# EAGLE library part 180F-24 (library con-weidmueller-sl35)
WEIDMUELLER CLAMP CONNECTOR

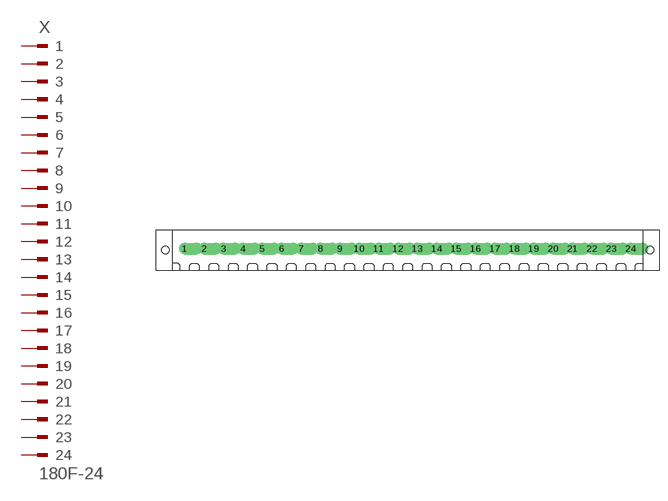
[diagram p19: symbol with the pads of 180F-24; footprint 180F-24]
Designator prefix X

## 180F-24  [180F-24]
1  1  pas
2  2  pas
3  3  pas
4  4  pas
5  5  pas
6  6  pas
7  7  pas
8  8  pas
9  9  pas
10  10  pas
11  11  pas
12  12  pas
13  13  pas
14  14  pas
15  15  pas
16  16  pas
17  17  pas
18  18  pas
19  19  pas
20  20  pas
21  21  pas
22  22  pas
23  23  pas
24  24  pas

## Footprint 180F-24 (pad centres in mm)
WEIDMUELLER CLAMP CONNECTOR
drill 1.422 offset: 1 -40.25,0; 2 -36.75,0; 3 -33.25,0; 4 -29.75,0; 5 -26.25,0; 6 -22.75,0; 7 -19.25,0; 8 -15.75,0; 9 -12.25,0; 10 -8.75,0; 11 -5.25,0; 12 -1.75,0; 13 1.75,0; 14 5.25,0; 15 8.75,0; 16 12.25,0; 17 15.75,0; 18 19.25,0; 19 22.75,0; 20 26.25,0; 21 29.75,0; 22 33.25,0; 23 36.75,0; 24 40.25,0
hole 1.422 at -43.75,-0.25
hole 1.422 at 43.75,-0.25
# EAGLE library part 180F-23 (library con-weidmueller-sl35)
WEIDMUELLER CLAMP CONNECTOR

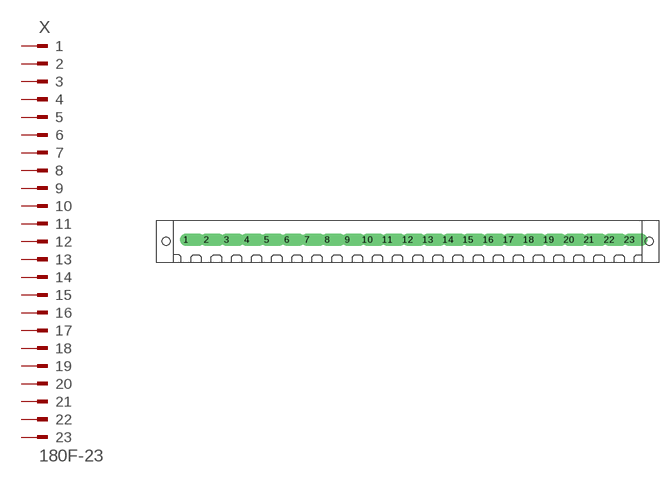
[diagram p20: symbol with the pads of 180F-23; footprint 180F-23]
Designator prefix X

## 180F-23  [180F-23]
1  1  pas
2  2  pas
3  3  pas
4  4  pas
5  5  pas
6  6  pas
7  7  pas
8  8  pas
9  9  pas
10  10  pas
11  11  pas
12  12  pas
13  13  pas
14  14  pas
15  15  pas
16  16  pas
17  17  pas
18  18  pas
19  19  pas
20  20  pas
21  21  pas
22  22  pas
23  23  pas

## Footprint 180F-23 (pad centres in mm)
WEIDMUELLER CLAMP CONNECTOR
drill 1.422 offset: 1 -38.5,0; 2 -35,0; 3 -31.5,0; 4 -28,0; 5 -24.5,0; 6 -21,0; 7 -17.5,0; 8 -14,0; 9 -10.5,0; 10 -7,0; 11 -3.5,0; 12 0,0; 13 3.5,0; 14 7,0; 15 10.5,0; 16 14,0; 17 17.5,0; 18 21,0; 19 24.5,0; 20 28,0; 21 31.5,0; 22 35,0; 23 38.5,0
hole 1.422 at -42,-0.25
hole 1.422 at 42,-0.25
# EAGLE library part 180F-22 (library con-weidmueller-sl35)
WEIDMUELLER CLAMP CONNECTOR

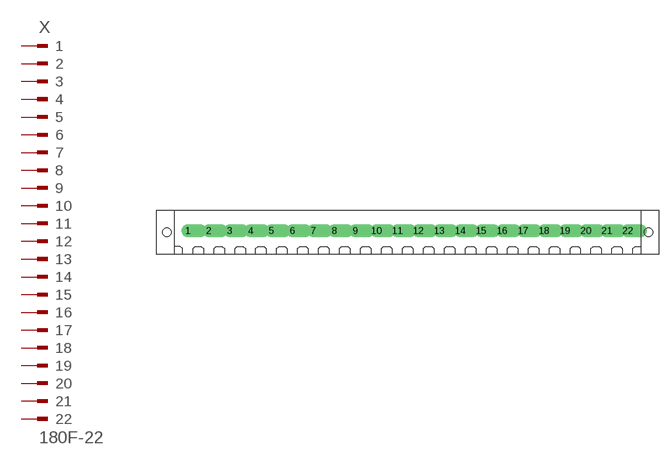
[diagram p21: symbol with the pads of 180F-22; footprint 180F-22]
Designator prefix X

## 180F-22  [180F-22]
1  1  pas
2  2  pas
3  3  pas
4  4  pas
5  5  pas
6  6  pas
7  7  pas
8  8  pas
9  9  pas
10  10  pas
11  11  pas
12  12  pas
13  13  pas
14  14  pas
15  15  pas
16  16  pas
17  17  pas
18  18  pas
19  19  pas
20  20  pas
21  21  pas
22  22  pas

## Footprint 180F-22 (pad centres in mm)
WEIDMUELLER CLAMP CONNECTOR
drill 1.422 offset: 1 -36.75,0; 2 -33.25,0; 3 -29.75,0; 4 -26.25,0; 5 -22.75,0; 6 -19.25,0; 7 -15.75,0; 8 -12.25,0; 9 -8.75,0; 10 -5.25,0; 11 -1.75,0; 12 1.75,0; 13 5.25,0; 14 8.75,0; 15 12.25,0; 16 15.75,0; 17 19.25,0; 18 22.75,0; 19 26.25,0; 20 29.75,0; 21 33.25,0; 22 36.75,0
hole 1.422 at -40.25,-0.25
hole 1.422 at 40.25,-0.25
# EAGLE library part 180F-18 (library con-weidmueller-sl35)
WEIDMUELLER CLAMP CONNECTOR

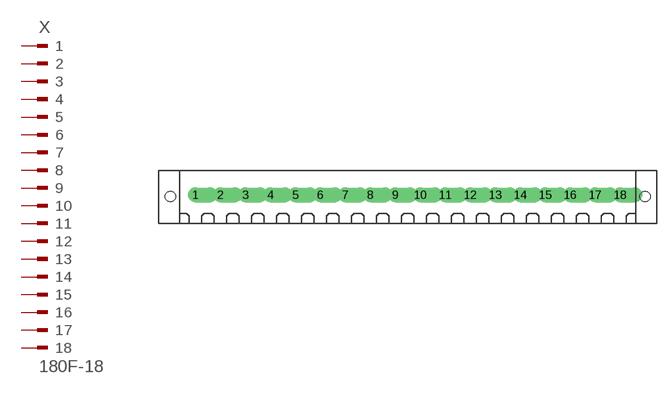
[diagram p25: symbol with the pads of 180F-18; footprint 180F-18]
Designator prefix X

## 180F-18  [180F-18]
1  1  pas
2  2  pas
3  3  pas
4  4  pas
5  5  pas
6  6  pas
7  7  pas
8  8  pas
9  9  pas
10  10  pas
11  11  pas
12  12  pas
13  13  pas
14  14  pas
15  15  pas
16  16  pas
17  17  pas
18  18  pas

## Footprint 180F-18 (pad centres in mm)
WEIDMUELLER CLAMP CONNECTOR
drill 1.422 offset: 1 -29.75,0; 2 -26.25,0; 3 -22.75,0; 4 -19.25,0; 5 -15.75,0; 6 -12.25,0; 7 -8.75,0; 8 -5.25,0; 9 -1.75,0; 10 1.75,0; 11 5.25,0; 12 8.75,0; 13 12.25,0; 14 15.75,0; 15 19.25,0; 16 22.75,0; 17 26.25,0; 18 29.75,0
hole 1.422 at -33.25,-0.25
hole 1.422 at 33.25,-0.25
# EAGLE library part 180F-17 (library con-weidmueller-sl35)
WEIDMUELLER CLAMP CONNECTOR

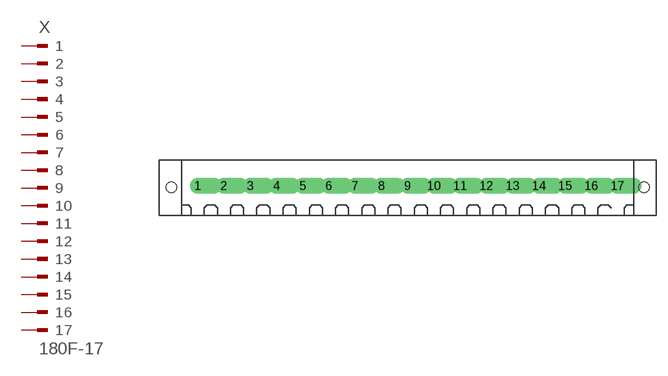
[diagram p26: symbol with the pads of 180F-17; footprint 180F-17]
Designator prefix X

## 180F-17  [180F-17]
1  1  pas
2  2  pas
3  3  pas
4  4  pas
5  5  pas
6  6  pas
7  7  pas
8  8  pas
9  9  pas
10  10  pas
11  11  pas
12  12  pas
13  13  pas
14  14  pas
15  15  pas
16  16  pas
17  17  pas

## Footprint 180F-17 (pad centres in mm)
WEIDMUELLER CLAMP CONNECTOR
drill 1.422 offset: 1 -28,0; 2 -24.5,0; 3 -21,0; 4 -17.5,0; 5 -14,0; 6 -10.5,0; 7 -7,0; 8 -3.5,0; 9 0,0; 10 3.5,0; 11 7,0; 12 10.5,0; 13 14,0; 14 17.5,0; 15 21,0; 16 24.5,0; 17 28,0
hole 1.422 at -31.5,-0.25
hole 1.422 at 31.5,-0.25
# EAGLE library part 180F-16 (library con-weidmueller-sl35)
WEIDMUELLER CLAMP CONNECTOR

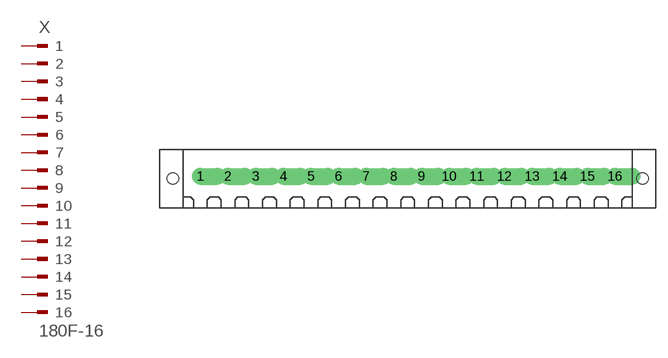
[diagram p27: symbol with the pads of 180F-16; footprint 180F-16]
Designator prefix X

## 180F-16  [180F-16]
1  1  pas
2  2  pas
3  3  pas
4  4  pas
5  5  pas
6  6  pas
7  7  pas
8  8  pas
9  9  pas
10  10  pas
11  11  pas
12  12  pas
13  13  pas
14  14  pas
15  15  pas
16  16  pas

## Footprint 180F-16 (pad centres in mm)
WEIDMUELLER CLAMP CONNECTOR
drill 1.422 offset: 1 -26.25,0; 2 -22.75,0; 3 -19.25,0; 4 -15.75,0; 5 -12.25,0; 6 -8.75,0; 7 -5.25,0; 8 -1.75,0; 9 1.75,0; 10 5.25,0; 11 8.75,0; 12 12.25,0; 13 15.75,0; 14 19.25,0; 15 22.75,0; 16 26.25,0
hole 1.422 at -29.75,-0.25
hole 1.422 at 29.75,-0.25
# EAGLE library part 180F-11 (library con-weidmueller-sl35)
WEIDMUELLER CLAMP CONNECTOR

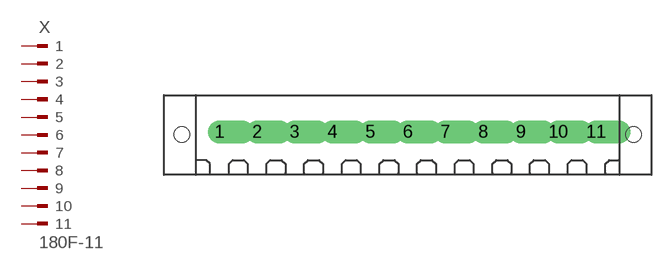
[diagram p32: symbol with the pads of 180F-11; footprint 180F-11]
Designator prefix X

## 180F-11  [180F-11]
1  1  pas
2  2  pas
3  3  pas
4  4  pas
5  5  pas
6  6  pas
7  7  pas
8  8  pas
9  9  pas
10  10  pas
11  11  pas

## Footprint 180F-11 (pad centres in mm)
WEIDMUELLER CLAMP CONNECTOR
drill 1.422 offset: 1 -17.5,0; 2 -14,0; 3 -10.5,0; 4 -7,0; 5 -3.5,0; 6 0,0; 7 3.5,0; 8 7,0; 9 10.5,0; 10 14,0; 11 17.5,0
hole 1.422 at -21,-0.25
hole 1.422 at 21,-0.25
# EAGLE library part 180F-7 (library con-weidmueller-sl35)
WEIDMUELLER CLAMP CONNECTOR

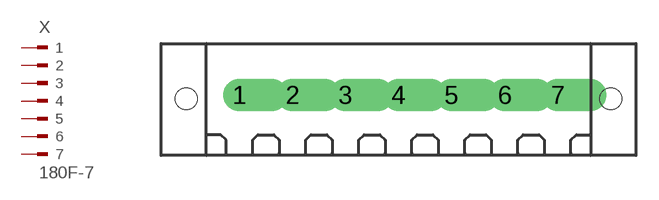
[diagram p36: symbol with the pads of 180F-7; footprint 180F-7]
Designator prefix X

## 180F-7  [180F-7]
1  1  pas
2  2  pas
3  3  pas
4  4  pas
5  5  pas
6  6  pas
7  7  pas

## Footprint 180F-7 (pad centres in mm)
WEIDMUELLER CLAMP CONNECTOR
drill 1.422 offset: 1 -10.5,0; 2 -7,0; 3 -3.5,0; 4 0,0; 5 3.5,0; 6 7,0; 7 10.5,0
hole 1.422 at -14,-0.25
hole 1.422 at 14,-0.25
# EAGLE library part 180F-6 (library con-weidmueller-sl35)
WEIDMUELLER CLAMP CONNECTOR

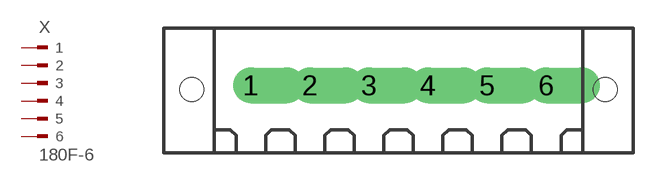
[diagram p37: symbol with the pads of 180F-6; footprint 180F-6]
Designator prefix X

## 180F-6  [180F-6]
1  1  pas
2  2  pas
3  3  pas
4  4  pas
5  5  pas
6  6  pas

## Footprint 180F-6 (pad centres in mm)
WEIDMUELLER CLAMP CONNECTOR
drill 1.422 offset: 1 -8.75,0; 2 -5.25,0; 3 -1.75,0; 4 1.75,0; 5 5.25,0; 6 8.75,0
hole 1.422 at -12.25,-0.25
hole 1.422 at 12.25,-0.25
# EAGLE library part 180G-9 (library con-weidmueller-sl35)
WEIDMUELLER CLAMP CONNECTOR

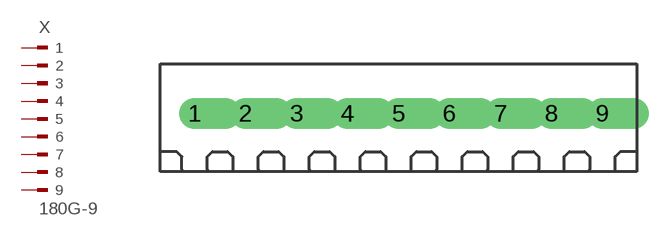
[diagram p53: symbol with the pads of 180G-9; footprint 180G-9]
Designator prefix X

## 180G-9  [180G-9]
1  1  pas
2  2  pas
3  3  pas
4  4  pas
5  5  pas
6  6  pas
7  7  pas
8  8  pas
9  9  pas

## Footprint 180G-9 (pad centres in mm)
WEIDMUELLER CLAMP CONNECTOR
drill 1.422 offset: 1 -14,0; 2 -10.5,0; 3 -7,0; 4 -3.5,0; 5 0,0; 6 3.5,0; 7 7,0; 8 10.5,0; 9 14,0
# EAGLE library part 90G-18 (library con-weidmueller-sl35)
WEIDMUELLER CLAMP CONNECTOR

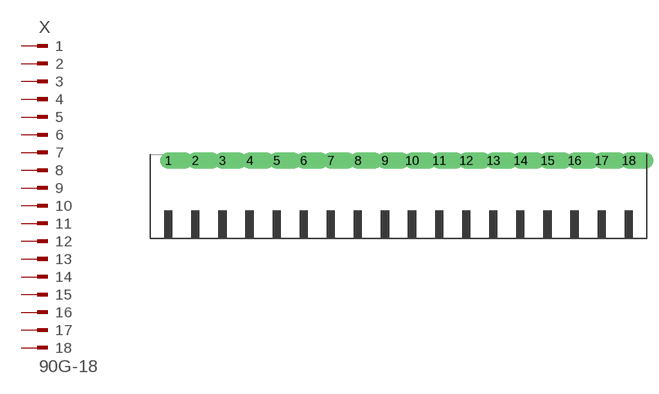
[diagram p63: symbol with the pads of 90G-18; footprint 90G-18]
Designator prefix X

## 90G-18  [90G-18]
1  1  pas
2  2  pas
3  3  pas
4  4  pas
5  5  pas
6  6  pas
7  7  pas
8  8  pas
9  9  pas
10  10  pas
11  11  pas
12  12  pas
13  13  pas
14  14  pas
15  15  pas
16  16  pas
17  17  pas
18  18  pas

## Footprint 90G-18 (pad centres in mm)
WEIDMUELLER CLAMP CONNECTOR
drill 1.422 offset: 1 -29.75,5.25; 2 -26.25,5.25; 3 -22.75,5.25; 4 -19.25,5.25; 5 -15.75,5.25; 6 -12.25,5.25; 7 -8.75,5.25; 8 -5.25,5.25; 9 -1.75,5.25; 10 1.75,5.25; 11 5.25,5.25; 12 8.75,5.25; 13 12.25,5.25; 14 15.75,5.25; 15 19.25,5.25; 16 22.75,5.25; 17 26.25,5.25; 18 29.75,5.25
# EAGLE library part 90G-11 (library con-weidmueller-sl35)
WEIDMUELLER CLAMP CONNECTOR

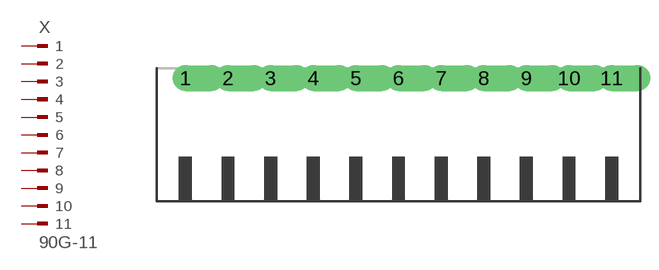
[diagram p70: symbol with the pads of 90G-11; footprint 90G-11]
Designator prefix X

## 90G-11  [90G-11]
1  1  pas
2  2  pas
3  3  pas
4  4  pas
5  5  pas
6  6  pas
7  7  pas
8  8  pas
9  9  pas
10  10  pas
11  11  pas

## Footprint 90G-11 (pad centres in mm)
WEIDMUELLER CLAMP CONNECTOR
drill 1.422 offset: 1 -17.5,5.25; 2 -14,5.25; 3 -10.5,5.25; 4 -7,5.25; 5 -3.5,5.25; 6 0,5.25; 7 3.5,5.25; 8 7,5.25; 9 10.5,5.25; 10 14,5.25; 11 17.5,5.25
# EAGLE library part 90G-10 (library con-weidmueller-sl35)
WEIDMUELLER CLAMP CONNECTOR

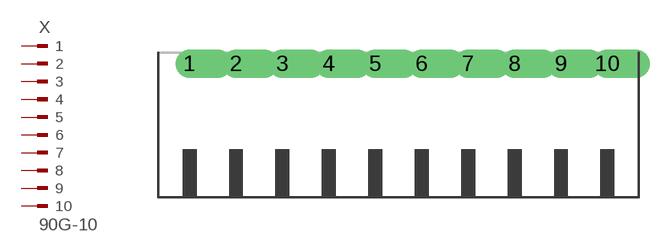
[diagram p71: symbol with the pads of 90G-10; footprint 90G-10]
Designator prefix X

## 90G-10  [90G-10]
1  1  pas
2  2  pas
3  3  pas
4  4  pas
5  5  pas
6  6  pas
7  7  pas
8  8  pas
9  9  pas
10  10  pas

## Footprint 90G-10 (pad centres in mm)
WEIDMUELLER CLAMP CONNECTOR
drill 1.422 offset: 1 -15.75,5.25; 2 -12.25,5.25; 3 -8.75,5.25; 4 -5.25,5.25; 5 -1.75,5.25; 6 1.75,5.25; 7 5.25,5.25; 8 8.75,5.25; 9 12.25,5.25; 10 15.75,5.25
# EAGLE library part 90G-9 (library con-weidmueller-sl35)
WEIDMUELLER CLAMP CONNECTOR

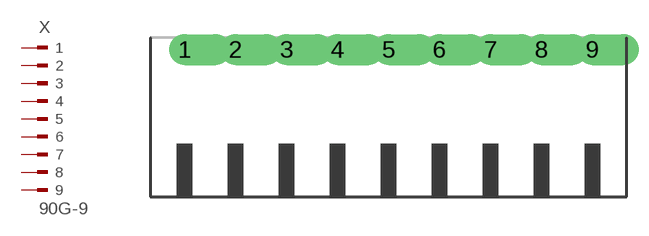
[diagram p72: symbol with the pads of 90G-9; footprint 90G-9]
Designator prefix X

## 90G-9  [90G-9]
1  1  pas
2  2  pas
3  3  pas
4  4  pas
5  5  pas
6  6  pas
7  7  pas
8  8  pas
9  9  pas

## Footprint 90G-9 (pad centres in mm)
WEIDMUELLER CLAMP CONNECTOR
drill 1.422 offset: 1 -14,5.25; 2 -10.5,5.25; 3 -7,5.25; 4 -3.5,5.25; 5 0,5.25; 6 3.5,5.25; 7 7,5.25; 8 10.5,5.25; 9 14,5.25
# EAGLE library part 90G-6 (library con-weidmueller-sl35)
WEIDMUELLER CLAMP CONNECTOR

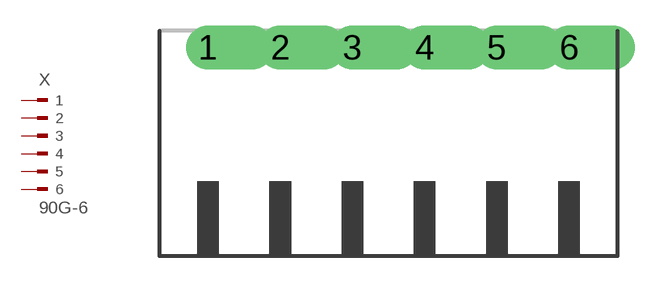
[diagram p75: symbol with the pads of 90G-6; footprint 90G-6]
Designator prefix X

## 90G-6  [90G-6]
1  1  pas
2  2  pas
3  3  pas
4  4  pas
5  5  pas
6  6  pas

## Footprint 90G-6 (pad centres in mm)
WEIDMUELLER CLAMP CONNECTOR
drill 1.422 offset: 1 -8.75,5.25; 2 -5.25,5.25; 3 -1.75,5.25; 4 1.75,5.25; 5 5.25,5.25; 6 8.75,5.25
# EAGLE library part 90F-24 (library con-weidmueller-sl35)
WEIDMUELLER CLAMP CONNECTOR

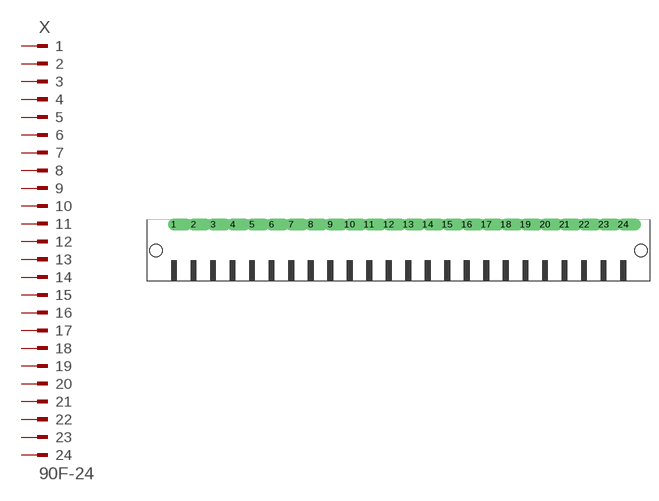
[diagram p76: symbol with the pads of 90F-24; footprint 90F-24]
Designator prefix X

## 90F-24  [90F-24]
1  1  pas
2  2  pas
3  3  pas
4  4  pas
5  5  pas
6  6  pas
7  7  pas
8  8  pas
9  9  pas
10  10  pas
11  11  pas
12  12  pas
13  13  pas
14  14  pas
15  15  pas
16  16  pas
17  17  pas
18  18  pas
19  19  pas
20  20  pas
21  21  pas
22  22  pas
23  23  pas
24  24  pas

## Footprint 90F-24 (pad centres in mm)
WEIDMUELLER CLAMP CONNECTOR
drill 1.422 offset: 1 -40.25,5.25; 2 -36.75,5.25; 3 -33.25,5.25; 4 -29.75,5.25; 5 -26.25,5.25; 6 -22.75,5.25; 7 -19.25,5.25; 8 -15.75,5.25; 9 -12.25,5.25; 10 -8.75,5.25; 11 -5.25,5.25; 12 -1.75,5.25; 13 1.75,5.25; 14 5.25,5.25; 15 8.75,5.25; 16 12.25,5.25; 17 15.75,5.25; 18 19.25,5.25; 19 22.75,5.25; 20 26.25,5.25; 21 29.75,5.25; 22 33.25,5.25; 23 36.75,5.25; 24 40.25,5.25
hole 2.3 at 43.45,0.55
hole 2.3 at -43.45,0.55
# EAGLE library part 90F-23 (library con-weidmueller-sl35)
WEIDMUELLER CLAMP CONNECTOR

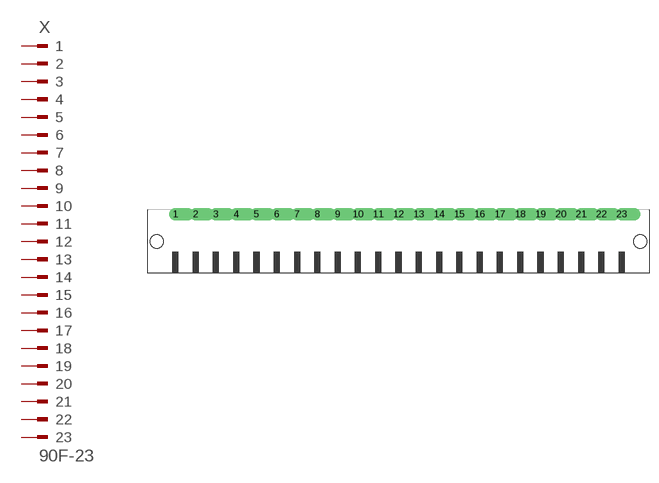
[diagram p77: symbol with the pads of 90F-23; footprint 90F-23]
Designator prefix X

## 90F-23  [90F-23]
1  1  pas
2  2  pas
3  3  pas
4  4  pas
5  5  pas
6  6  pas
7  7  pas
8  8  pas
9  9  pas
10  10  pas
11  11  pas
12  12  pas
13  13  pas
14  14  pas
15  15  pas
16  16  pas
17  17  pas
18  18  pas
19  19  pas
20  20  pas
21  21  pas
22  22  pas
23  23  pas

## Footprint 90F-23 (pad centres in mm)
WEIDMUELLER CLAMP CONNECTOR
drill 1.422 offset: 1 -38.5,5.25; 2 -35,5.25; 3 -31.5,5.25; 4 -28,5.25; 5 -24.5,5.25; 6 -21,5.25; 7 -17.5,5.25; 8 -14,5.25; 9 -10.5,5.25; 10 -7,5.25; 11 -3.5,5.25; 12 0,5.25; 13 3.5,5.25; 14 7,5.25; 15 10.5,5.25; 16 14,5.25; 17 17.5,5.25; 18 21,5.25; 19 24.5,5.25; 20 28,5.25; 21 31.5,5.25; 22 35,5.25; 23 38.5,5.25
hole 2.3 at 41.7,0.55
hole 2.3 at -41.7,0.55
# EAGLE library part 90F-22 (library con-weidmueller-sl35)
WEIDMUELLER CLAMP CONNECTOR

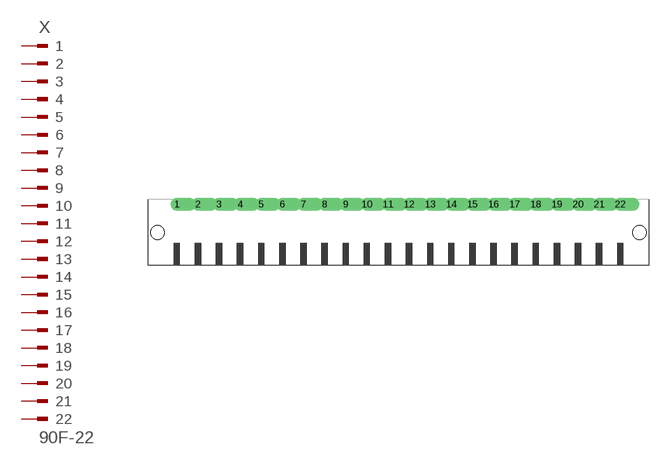
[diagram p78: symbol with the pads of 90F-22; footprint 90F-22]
Designator prefix X

## 90F-22  [90F-22]
1  1  pas
2  2  pas
3  3  pas
4  4  pas
5  5  pas
6  6  pas
7  7  pas
8  8  pas
9  9  pas
10  10  pas
11  11  pas
12  12  pas
13  13  pas
14  14  pas
15  15  pas
16  16  pas
17  17  pas
18  18  pas
19  19  pas
20  20  pas
21  21  pas
22  22  pas

## Footprint 90F-22 (pad centres in mm)
WEIDMUELLER CLAMP CONNECTOR
drill 1.422 offset: 1 -36.75,5.25; 2 -33.25,5.25; 3 -29.75,5.25; 4 -26.25,5.25; 5 -22.75,5.25; 6 -19.25,5.25; 7 -15.75,5.25; 8 -12.25,5.25; 9 -8.75,5.25; 10 -5.25,5.25; 11 -1.75,5.25; 12 1.75,5.25; 13 5.25,5.25; 14 8.75,5.25; 15 12.25,5.25; 16 15.75,5.25; 17 19.25,5.25; 18 22.75,5.25; 19 26.25,5.25; 20 29.75,5.25; 21 33.25,5.25; 22 36.75,5.25
hole 2.3 at 39.95,0.55
hole 2.3 at -39.95,0.55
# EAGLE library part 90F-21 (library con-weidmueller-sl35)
WEIDMUELLER CLAMP CONNECTOR

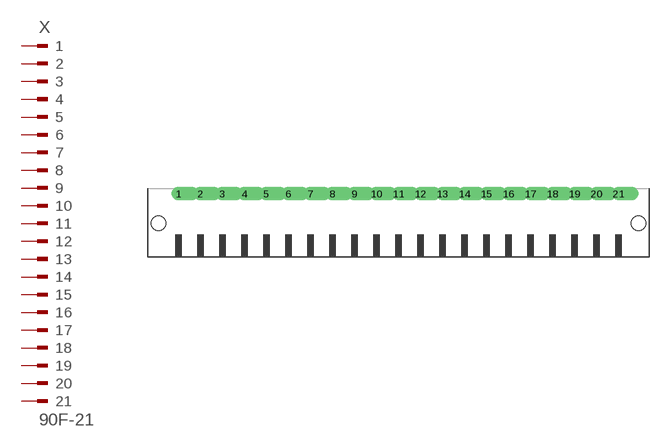
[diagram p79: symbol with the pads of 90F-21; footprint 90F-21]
Designator prefix X

## 90F-21  [90F-21]
1  1  pas
2  2  pas
3  3  pas
4  4  pas
5  5  pas
6  6  pas
7  7  pas
8  8  pas
9  9  pas
10  10  pas
11  11  pas
12  12  pas
13  13  pas
14  14  pas
15  15  pas
16  16  pas
17  17  pas
18  18  pas
19  19  pas
20  20  pas
21  21  pas

## Footprint 90F-21 (pad centres in mm)
WEIDMUELLER CLAMP CONNECTOR
drill 1.422 offset: 1 -35,5.25; 2 -31.5,5.25; 3 -28,5.25; 4 -24.5,5.25; 5 -21,5.25; 6 -17.5,5.25; 7 -14,5.25; 8 -10.5,5.25; 9 -7,5.25; 10 -3.5,5.25; 11 0,5.25; 12 3.5,5.25; 13 7,5.25; 14 10.5,5.25; 15 14,5.25; 16 17.5,5.25; 17 21,5.25; 18 24.5,5.25; 19 28,5.25; 20 31.5,5.25; 21 35,5.25
hole 2.3 at 38.2,0.55
hole 2.3 at -38.2,0.55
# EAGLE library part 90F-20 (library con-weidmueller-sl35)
WEIDMUELLER CLAMP CONNECTOR

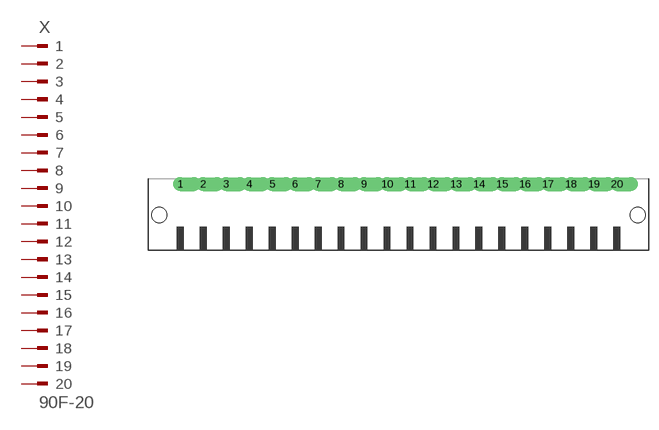
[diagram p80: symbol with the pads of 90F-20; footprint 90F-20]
Designator prefix X

## 90F-20  [90F-20]
1  1  pas
2  2  pas
3  3  pas
4  4  pas
5  5  pas
6  6  pas
7  7  pas
8  8  pas
9  9  pas
10  10  pas
11  11  pas
12  12  pas
13  13  pas
14  14  pas
15  15  pas
16  16  pas
17  17  pas
18  18  pas
19  19  pas
20  20  pas

## Footprint 90F-20 (pad centres in mm)
WEIDMUELLER CLAMP CONNECTOR
drill 1.422 offset: 1 -33.25,5.25; 2 -29.75,5.25; 3 -26.25,5.25; 4 -22.75,5.25; 5 -19.25,5.25; 6 -15.75,5.25; 7 -12.25,5.25; 8 -8.75,5.25; 9 -5.25,5.25; 10 -1.75,5.25; 11 1.75,5.25; 12 5.25,5.25; 13 8.75,5.25; 14 12.25,5.25; 15 15.75,5.25; 16 19.25,5.25; 17 22.75,5.25; 18 26.25,5.25; 19 29.75,5.25; 20 33.25,5.25
hole 2.3 at 36.45,0.55
hole 2.3 at -36.45,0.55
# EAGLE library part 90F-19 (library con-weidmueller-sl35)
WEIDMUELLER CLAMP CONNECTOR

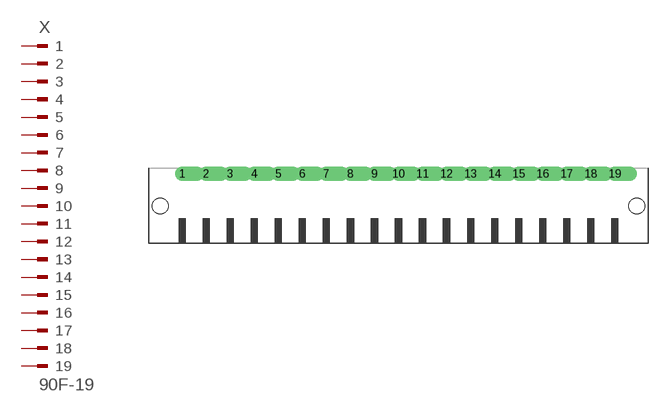
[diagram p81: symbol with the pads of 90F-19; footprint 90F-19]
Designator prefix X

## 90F-19  [90F-19]
1  1  pas
2  2  pas
3  3  pas
4  4  pas
5  5  pas
6  6  pas
7  7  pas
8  8  pas
9  9  pas
10  10  pas
11  11  pas
12  12  pas
13  13  pas
14  14  pas
15  15  pas
16  16  pas
17  17  pas
18  18  pas
19  19  pas

## Footprint 90F-19 (pad centres in mm)
WEIDMUELLER CLAMP CONNECTOR
drill 1.422 offset: 1 -31.5,5.25; 2 -28,5.25; 3 -24.5,5.25; 4 -21,5.25; 5 -17.5,5.25; 6 -14,5.25; 7 -10.5,5.25; 8 -7,5.25; 9 -3.5,5.25; 10 0,5.25; 11 3.5,5.25; 12 7,5.25; 13 10.5,5.25; 14 14,5.25; 15 17.5,5.25; 16 21,5.25; 17 24.5,5.25; 18 28,5.25; 19 31.5,5.25
hole 2.3 at 34.7,0.55
hole 2.3 at -34.7,0.55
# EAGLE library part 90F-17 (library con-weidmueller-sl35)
WEIDMUELLER CLAMP CONNECTOR

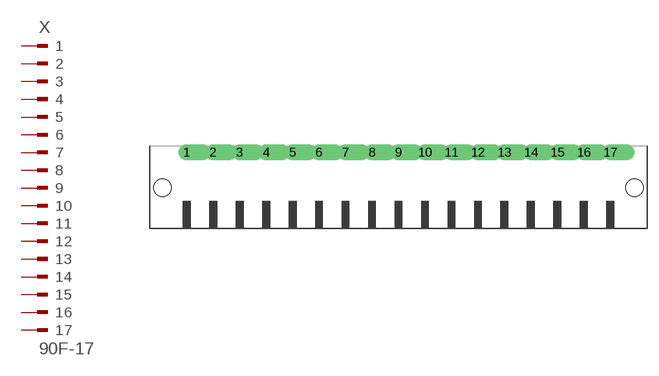
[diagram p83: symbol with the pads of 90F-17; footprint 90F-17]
Designator prefix X

## 90F-17  [90F-17]
1  1  pas
2  2  pas
3  3  pas
4  4  pas
5  5  pas
6  6  pas
7  7  pas
8  8  pas
9  9  pas
10  10  pas
11  11  pas
12  12  pas
13  13  pas
14  14  pas
15  15  pas
16  16  pas
17  17  pas

## Footprint 90F-17 (pad centres in mm)
WEIDMUELLER CLAMP CONNECTOR
drill 1.422 offset: 1 -28,5.25; 2 -24.5,5.25; 3 -21,5.25; 4 -17.5,5.25; 5 -14,5.25; 6 -10.5,5.25; 7 -7,5.25; 8 -3.5,5.25; 9 0,5.25; 10 3.5,5.25; 11 7,5.25; 12 10.5,5.25; 13 14,5.25; 14 17.5,5.25; 15 21,5.25; 16 24.5,5.25; 17 28,5.25
hole 2.3 at 31.2,0.55
hole 2.3 at -31.2,0.55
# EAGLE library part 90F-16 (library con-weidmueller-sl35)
WEIDMUELLER CLAMP CONNECTOR

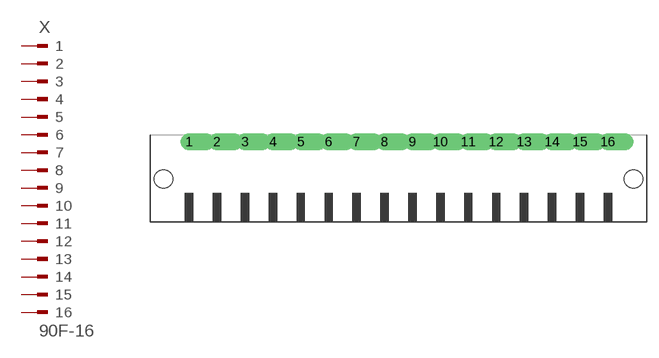
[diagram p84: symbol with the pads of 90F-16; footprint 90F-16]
Designator prefix X

## 90F-16  [90F-16]
1  1  pas
2  2  pas
3  3  pas
4  4  pas
5  5  pas
6  6  pas
7  7  pas
8  8  pas
9  9  pas
10  10  pas
11  11  pas
12  12  pas
13  13  pas
14  14  pas
15  15  pas
16  16  pas

## Footprint 90F-16 (pad centres in mm)
WEIDMUELLER CLAMP CONNECTOR
drill 1.422 offset: 1 -26.25,5.25; 2 -22.75,5.25; 3 -19.25,5.25; 4 -15.75,5.25; 5 -12.25,5.25; 6 -8.75,5.25; 7 -5.25,5.25; 8 -1.75,5.25; 9 1.75,5.25; 10 5.25,5.25; 11 8.75,5.25; 12 12.25,5.25; 13 15.75,5.25; 14 19.25,5.25; 15 22.75,5.25; 16 26.25,5.25
hole 2.3 at 29.45,0.55
hole 2.3 at -29.45,0.55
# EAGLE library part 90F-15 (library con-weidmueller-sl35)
WEIDMUELLER CLAMP CONNECTOR

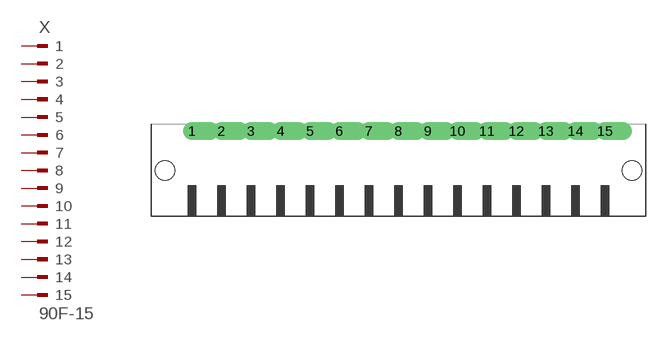
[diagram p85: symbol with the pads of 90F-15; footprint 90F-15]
Designator prefix X

## 90F-15  [90F-15]
1  1  pas
2  2  pas
3  3  pas
4  4  pas
5  5  pas
6  6  pas
7  7  pas
8  8  pas
9  9  pas
10  10  pas
11  11  pas
12  12  pas
13  13  pas
14  14  pas
15  15  pas

## Footprint 90F-15 (pad centres in mm)
WEIDMUELLER CLAMP CONNECTOR
drill 1.422 offset: 1 -24.5,5.25; 2 -21,5.25; 3 -17.5,5.25; 4 -14,5.25; 5 -10.5,5.25; 6 -7,5.25; 7 -3.5,5.25; 8 0,5.25; 9 3.5,5.25; 10 7,5.25; 11 10.5,5.25; 12 14,5.25; 13 17.5,5.25; 14 21,5.25; 15 24.5,5.25
hole 2.3 at 27.7,0.55
hole 2.3 at -27.7,0.55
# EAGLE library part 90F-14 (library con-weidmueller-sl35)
WEIDMUELLER CLAMP CONNECTOR

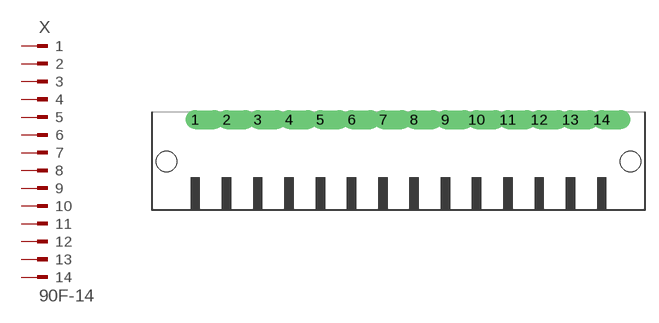
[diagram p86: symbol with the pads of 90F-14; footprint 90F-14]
Designator prefix X

## 90F-14  [90F-14]
1  1  pas
2  2  pas
3  3  pas
4  4  pas
5  5  pas
6  6  pas
7  7  pas
8  8  pas
9  9  pas
10  10  pas
11  11  pas
12  12  pas
13  13  pas
14  14  pas

## Footprint 90F-14 (pad centres in mm)
WEIDMUELLER CLAMP CONNECTOR
drill 1.422 offset: 1 -22.75,5.25; 2 -19.25,5.25; 3 -15.75,5.25; 4 -12.25,5.25; 5 -8.75,5.25; 6 -5.25,5.25; 7 -1.75,5.25; 8 1.75,5.25; 9 5.25,5.25; 10 8.75,5.25; 11 12.25,5.25; 12 15.75,5.25; 13 19.25,5.25; 14 22.75,5.25
hole 2.3 at 25.95,0.55
hole 2.3 at -25.95,0.55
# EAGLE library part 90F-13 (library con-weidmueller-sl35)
WEIDMUELLER CLAMP CONNECTOR

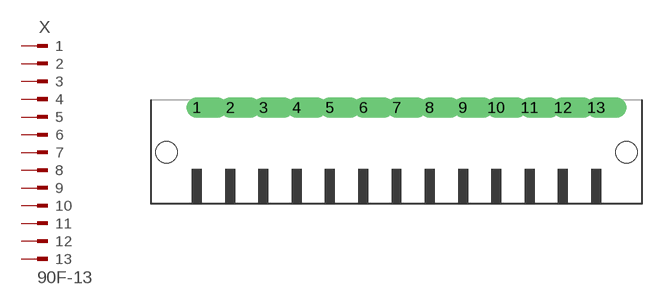
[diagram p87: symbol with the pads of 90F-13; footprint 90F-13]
Designator prefix X

## 90F-13  [90F-13]
1  1  pas
2  2  pas
3  3  pas
4  4  pas
5  5  pas
6  6  pas
7  7  pas
8  8  pas
9  9  pas
10  10  pas
11  11  pas
12  12  pas
13  13  pas

## Footprint 90F-13 (pad centres in mm)
WEIDMUELLER CLAMP CONNECTOR
drill 1.422 offset: 1 -21,5.25; 2 -17.5,5.25; 3 -14,5.25; 4 -10.5,5.25; 5 -7,5.25; 6 -3.5,5.25; 7 0,5.25; 8 3.5,5.25; 9 7,5.25; 10 10.5,5.25; 11 14,5.25; 12 17.5,5.25; 13 21,5.25
hole 2.3 at 24.2,0.55
hole 2.3 at -24.2,0.55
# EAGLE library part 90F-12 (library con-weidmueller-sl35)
WEIDMUELLER CLAMP CONNECTOR

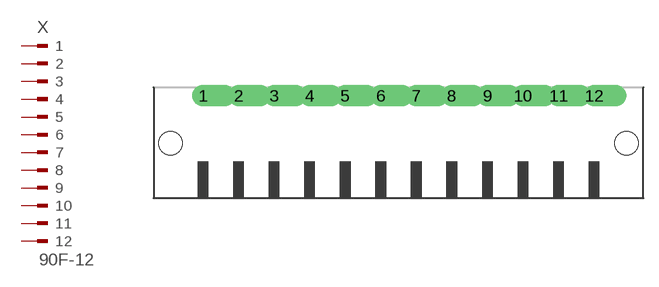
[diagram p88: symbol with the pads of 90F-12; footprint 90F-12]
Designator prefix X

## 90F-12  [90F-12]
1  1  pas
2  2  pas
3  3  pas
4  4  pas
5  5  pas
6  6  pas
7  7  pas
8  8  pas
9  9  pas
10  10  pas
11  11  pas
12  12  pas

## Footprint 90F-12 (pad centres in mm)
WEIDMUELLER CLAMP CONNECTOR
drill 1.422 offset: 1 -19.25,5.25; 2 -15.75,5.25; 3 -12.25,5.25; 4 -8.75,5.25; 5 -5.25,5.25; 6 -1.75,5.25; 7 1.75,5.25; 8 5.25,5.25; 9 8.75,5.25; 10 12.25,5.25; 11 15.75,5.25; 12 19.25,5.25
hole 2.3 at 22.45,0.55
hole 2.3 at -22.45,0.55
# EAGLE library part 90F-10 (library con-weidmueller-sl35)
WEIDMUELLER CLAMP CONNECTOR

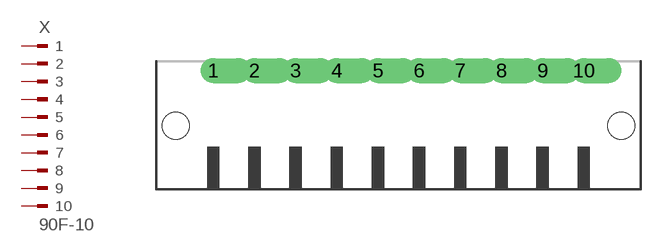
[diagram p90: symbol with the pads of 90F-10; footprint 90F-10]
Designator prefix X

## 90F-10  [90F-10]
1  1  pas
2  2  pas
3  3  pas
4  4  pas
5  5  pas
6  6  pas
7  7  pas
8  8  pas
9  9  pas
10  10  pas

## Footprint 90F-10 (pad centres in mm)
WEIDMUELLER CLAMP CONNECTOR
drill 1.422 offset: 1 -15.75,5.25; 2 -12.25,5.25; 3 -8.75,5.25; 4 -5.25,5.25; 5 -1.75,5.25; 6 1.75,5.25; 7 5.25,5.25; 8 8.75,5.25; 9 12.25,5.25; 10 15.75,5.25
hole 2.3 at 18.95,0.55
hole 2.3 at -18.95,0.55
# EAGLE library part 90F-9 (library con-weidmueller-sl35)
WEIDMUELLER CLAMP CONNECTOR

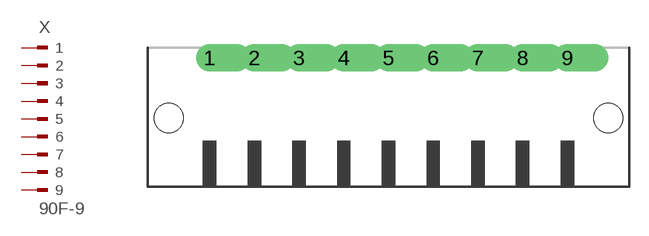
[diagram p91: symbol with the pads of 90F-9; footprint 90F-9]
Designator prefix X

## 90F-9  [90F-9]
1  1  pas
2  2  pas
3  3  pas
4  4  pas
5  5  pas
6  6  pas
7  7  pas
8  8  pas
9  9  pas

## Footprint 90F-9 (pad centres in mm)
WEIDMUELLER CLAMP CONNECTOR
drill 1.422 offset: 1 -14,5.25; 2 -10.5,5.25; 3 -7,5.25; 4 -3.5,5.25; 5 0,5.25; 6 3.5,5.25; 7 7,5.25; 8 10.5,5.25; 9 14,5.25
hole 2.3 at 17.2,0.55
hole 2.3 at -17.2,0.55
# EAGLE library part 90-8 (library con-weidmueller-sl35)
WEIDMUELLER CLAMP CONNECTOR

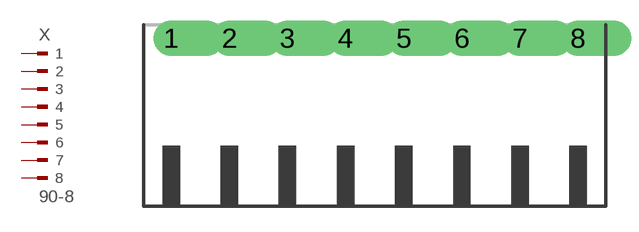
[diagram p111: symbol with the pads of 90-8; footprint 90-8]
Designator prefix X

## 90-8  [90-8]
1  1  pas
2  2  pas
3  3  pas
4  4  pas
5  5  pas
6  6  pas
7  7  pas
8  8  pas

## Footprint 90-8 (pad centres in mm)
WEIDMUELLER CLAMP CONNECTOR
drill 1.422 offset: 1 -12.25,5.25; 2 -8.75,5.25; 3 -5.25,5.25; 4 -1.75,5.25; 5 1.75,5.25; 6 5.25,5.25; 7 8.75,5.25; 8 12.25,5.25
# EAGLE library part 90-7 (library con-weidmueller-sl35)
WEIDMUELLER CLAMP CONNECTOR

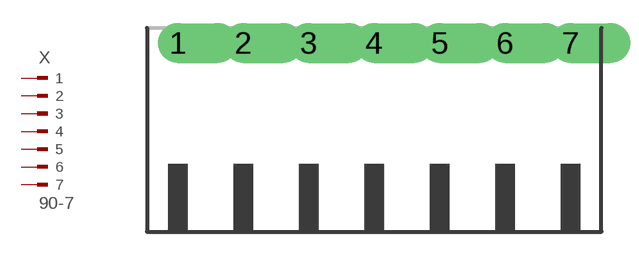
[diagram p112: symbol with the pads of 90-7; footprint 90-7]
Designator prefix X

## 90-7  [90-7]
1  1  pas
2  2  pas
3  3  pas
4  4  pas
5  5  pas
6  6  pas
7  7  pas

## Footprint 90-7 (pad centres in mm)
WEIDMUELLER CLAMP CONNECTOR
drill 1.422 offset: 1 -10.5,5.25; 2 -7,5.25; 3 -3.5,5.25; 4 0,5.25; 5 3.5,5.25; 6 7,5.25; 7 10.5,5.25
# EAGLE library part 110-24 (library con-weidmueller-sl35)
WEIDMUELLER CLAMP CONNECTOR

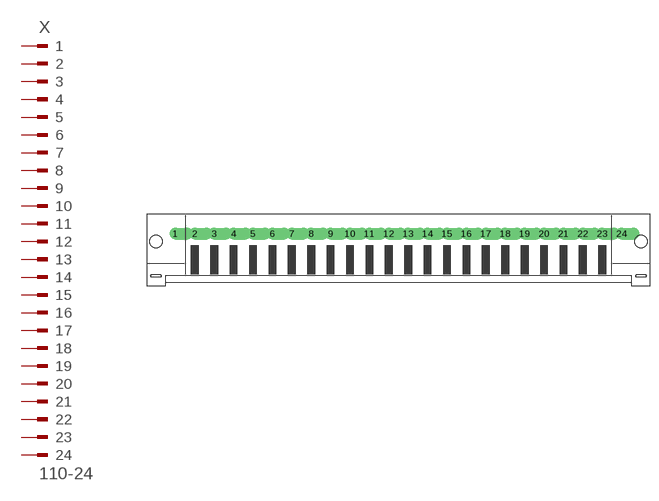
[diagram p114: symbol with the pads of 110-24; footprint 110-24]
Designator prefix X

## 110-24  [110-24]
1  1  pas
2  2  pas
3  3  pas
4  4  pas
5  5  pas
6  6  pas
7  7  pas
8  8  pas
9  9  pas
10  10  pas
11  11  pas
12  12  pas
13  13  pas
14  14  pas
15  15  pas
16  16  pas
17  17  pas
18  18  pas
19  19  pas
20  20  pas
21  21  pas
22  22  pas
23  23  pas
24  24  pas

## Footprint 110-24 (pad centres in mm)
WEIDMUELLER CLAMP CONNECTOR
drill 1.422 offset: 1 -40.25,1.75; 2 -36.75,1.75; 3 -33.25,1.75; 4 -29.75,1.75; 5 -26.25,1.75; 6 -22.75,1.75; 7 -19.25,1.75; 8 -15.75,1.75; 9 -12.25,1.75; 10 -8.75,1.75; 11 -5.25,1.75; 12 -1.75,1.75; 13 1.75,1.75; 14 5.25,1.75; 15 8.75,1.75; 16 12.25,1.75; 17 15.75,1.75; 18 19.25,1.75; 19 22.75,1.75; 20 26.25,1.75; 21 29.75,1.75; 22 33.25,1.75; 23 36.75,1.75; 24 40.25,1.75
hole 2.3 at -43.75,0.35
hole 2.3 at 43.75,0.35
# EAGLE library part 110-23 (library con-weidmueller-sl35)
WEIDMUELLER CLAMP CONNECTOR

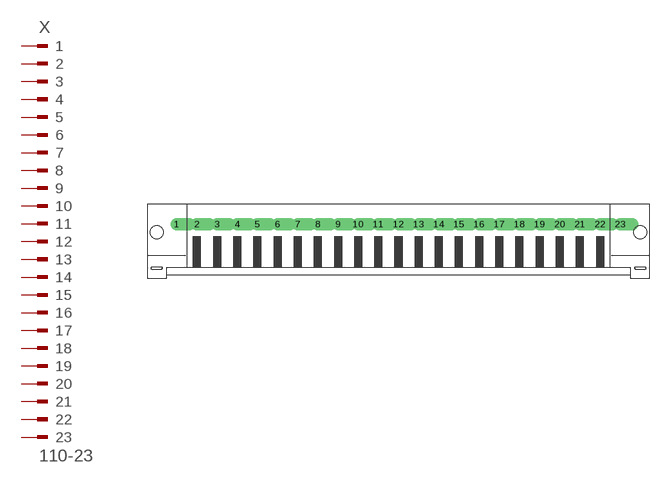
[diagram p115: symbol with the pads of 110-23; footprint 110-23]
Designator prefix X

## 110-23  [110-23]
1  1  pas
2  2  pas
3  3  pas
4  4  pas
5  5  pas
6  6  pas
7  7  pas
8  8  pas
9  9  pas
10  10  pas
11  11  pas
12  12  pas
13  13  pas
14  14  pas
15  15  pas
16  16  pas
17  17  pas
18  18  pas
19  19  pas
20  20  pas
21  21  pas
22  22  pas
23  23  pas

## Footprint 110-23 (pad centres in mm)
WEIDMUELLER CLAMP CONNECTOR
drill 1.422 offset: 1 -38.5,1.75; 2 -35,1.75; 3 -31.5,1.75; 4 -28,1.75; 5 -24.5,1.75; 6 -21,1.75; 7 -17.5,1.75; 8 -14,1.75; 9 -10.5,1.75; 10 -7,1.75; 11 -3.5,1.75; 12 0,1.75; 13 3.5,1.75; 14 7,1.75; 15 10.5,1.75; 16 14,1.75; 17 17.5,1.75; 18 21,1.75; 19 24.5,1.75; 20 28,1.75; 21 31.5,1.75; 22 35,1.75; 23 38.5,1.75
hole 2.3 at -42,0.35
hole 2.3 at 42,0.35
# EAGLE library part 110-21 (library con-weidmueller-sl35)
WEIDMUELLER CLAMP CONNECTOR

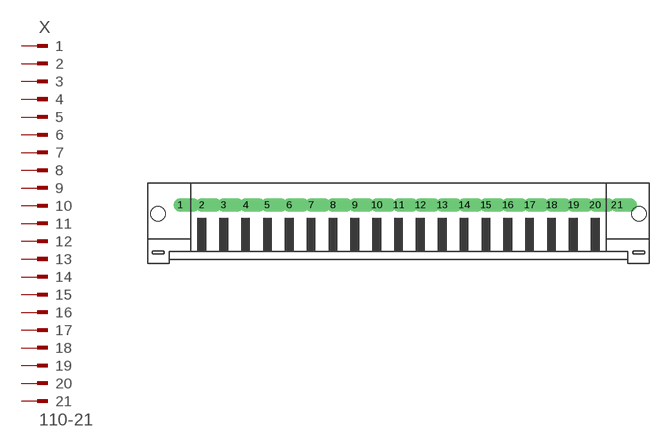
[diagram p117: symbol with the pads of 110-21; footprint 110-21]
Designator prefix X

## 110-21  [110-21]
1  1  pas
2  2  pas
3  3  pas
4  4  pas
5  5  pas
6  6  pas
7  7  pas
8  8  pas
9  9  pas
10  10  pas
11  11  pas
12  12  pas
13  13  pas
14  14  pas
15  15  pas
16  16  pas
17  17  pas
18  18  pas
19  19  pas
20  20  pas
21  21  pas

## Footprint 110-21 (pad centres in mm)
WEIDMUELLER CLAMP CONNECTOR
drill 1.422 offset: 1 -35,1.75; 2 -31.5,1.75; 3 -28,1.75; 4 -24.5,1.75; 5 -21,1.75; 6 -17.5,1.75; 7 -14,1.75; 8 -10.5,1.75; 9 -7,1.75; 10 -3.5,1.75; 11 0,1.75; 12 3.5,1.75; 13 7,1.75; 14 10.5,1.75; 15 14,1.75; 16 17.5,1.75; 17 21,1.75; 18 24.5,1.75; 19 28,1.75; 20 31.5,1.75; 21 35,1.75
hole 2.3 at -38.5,0.35
hole 2.3 at 38.5,0.35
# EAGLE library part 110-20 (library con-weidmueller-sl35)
WEIDMUELLER CLAMP CONNECTOR

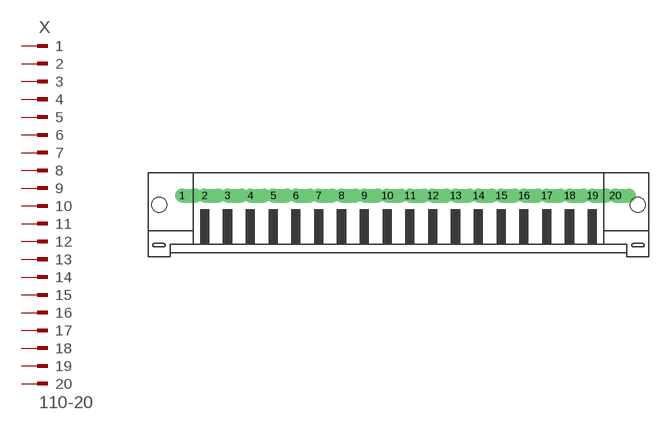
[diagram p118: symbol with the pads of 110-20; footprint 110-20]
Designator prefix X

## 110-20  [110-20]
1  1  pas
2  2  pas
3  3  pas
4  4  pas
5  5  pas
6  6  pas
7  7  pas
8  8  pas
9  9  pas
10  10  pas
11  11  pas
12  12  pas
13  13  pas
14  14  pas
15  15  pas
16  16  pas
17  17  pas
18  18  pas
19  19  pas
20  20  pas

## Footprint 110-20 (pad centres in mm)
WEIDMUELLER CLAMP CONNECTOR
drill 1.422 offset: 1 -33.25,1.75; 2 -29.75,1.75; 3 -26.25,1.75; 4 -22.75,1.75; 5 -19.25,1.75; 6 -15.75,1.75; 7 -12.25,1.75; 8 -8.75,1.75; 9 -5.25,1.75; 10 -1.75,1.75; 11 1.75,1.75; 12 5.25,1.75; 13 8.75,1.75; 14 12.25,1.75; 15 15.75,1.75; 16 19.25,1.75; 17 22.75,1.75; 18 26.25,1.75; 19 29.75,1.75; 20 33.25,1.75
hole 2.3 at -36.75,0.35
hole 2.3 at 36.75,0.35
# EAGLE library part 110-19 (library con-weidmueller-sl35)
WEIDMUELLER CLAMP CONNECTOR

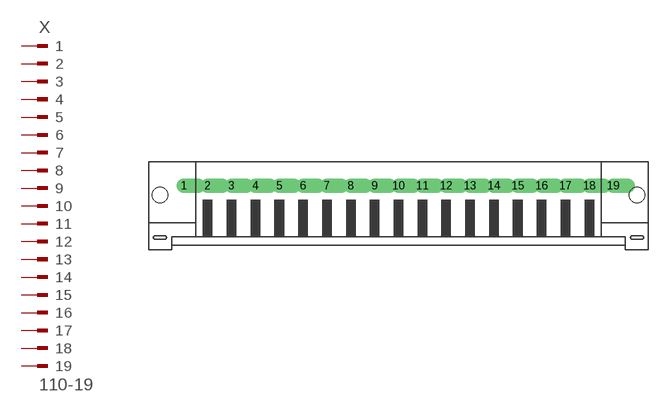
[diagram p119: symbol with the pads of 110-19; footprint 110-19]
Designator prefix X

## 110-19  [110-19]
1  1  pas
2  2  pas
3  3  pas
4  4  pas
5  5  pas
6  6  pas
7  7  pas
8  8  pas
9  9  pas
10  10  pas
11  11  pas
12  12  pas
13  13  pas
14  14  pas
15  15  pas
16  16  pas
17  17  pas
18  18  pas
19  19  pas

## Footprint 110-19 (pad centres in mm)
WEIDMUELLER CLAMP CONNECTOR
drill 1.422 offset: 1 -31.5,1.75; 2 -28,1.75; 3 -24.5,1.75; 4 -21,1.75; 5 -17.5,1.75; 6 -14,1.75; 7 -10.5,1.75; 8 -7,1.75; 9 -3.5,1.75; 10 0,1.75; 11 3.5,1.75; 12 7,1.75; 13 10.5,1.75; 14 14,1.75; 15 17.5,1.75; 16 21,1.75; 17 24.5,1.75; 18 28,1.75; 19 31.5,1.75
hole 2.3 at -35,0.35
hole 2.3 at 35,0.35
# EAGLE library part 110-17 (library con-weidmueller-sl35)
WEIDMUELLER CLAMP CONNECTOR

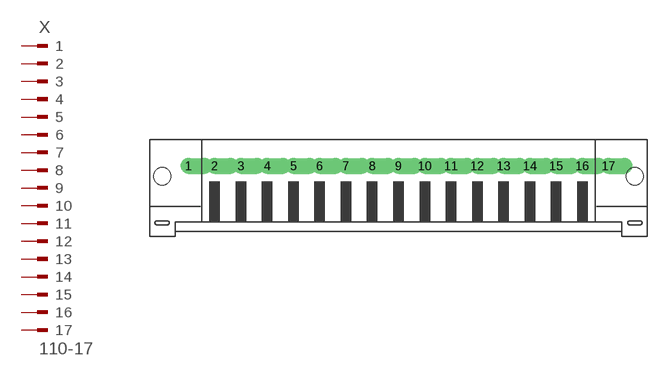
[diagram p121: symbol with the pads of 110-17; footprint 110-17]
Designator prefix X

## 110-17  [110-17]
1  1  pas
2  2  pas
3  3  pas
4  4  pas
5  5  pas
6  6  pas
7  7  pas
8  8  pas
9  9  pas
10  10  pas
11  11  pas
12  12  pas
13  13  pas
14  14  pas
15  15  pas
16  16  pas
17  17  pas

## Footprint 110-17 (pad centres in mm)
WEIDMUELLER CLAMP CONNECTOR
drill 1.422 offset: 1 -28,1.75; 2 -24.5,1.75; 3 -21,1.75; 4 -17.5,1.75; 5 -14,1.75; 6 -10.5,1.75; 7 -7,1.75; 8 -3.5,1.75; 9 0,1.75; 10 3.5,1.75; 11 7,1.75; 12 10.5,1.75; 13 14,1.75; 14 17.5,1.75; 15 21,1.75; 16 24.5,1.75; 17 28,1.75
hole 2.3 at -31.5,0.35
hole 2.3 at 31.5,0.35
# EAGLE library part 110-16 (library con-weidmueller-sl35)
WEIDMUELLER CLAMP CONNECTOR

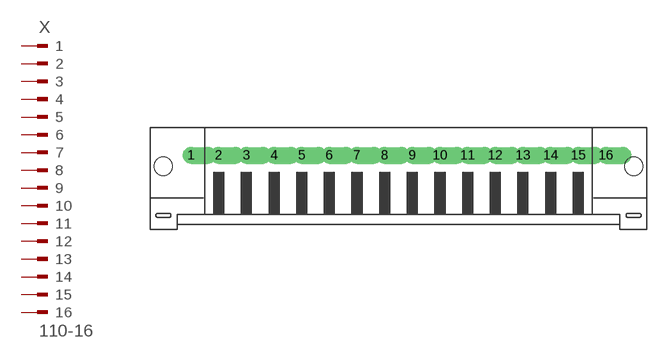
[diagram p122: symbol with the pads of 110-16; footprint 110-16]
Designator prefix X

## 110-16  [110-16]
1  1  pas
2  2  pas
3  3  pas
4  4  pas
5  5  pas
6  6  pas
7  7  pas
8  8  pas
9  9  pas
10  10  pas
11  11  pas
12  12  pas
13  13  pas
14  14  pas
15  15  pas
16  16  pas

## Footprint 110-16 (pad centres in mm)
WEIDMUELLER CLAMP CONNECTOR
drill 1.422 offset: 1 -26.25,1.75; 2 -22.75,1.75; 3 -19.25,1.75; 4 -15.75,1.75; 5 -12.25,1.75; 6 -8.75,1.75; 7 -5.25,1.75; 8 -1.75,1.75; 9 1.75,1.75; 10 5.25,1.75; 11 8.75,1.75; 12 12.25,1.75; 13 15.75,1.75; 14 19.25,1.75; 15 22.75,1.75; 16 26.25,1.75
hole 2.3 at -29.75,0.35
hole 2.3 at 29.75,0.35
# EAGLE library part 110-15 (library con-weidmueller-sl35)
WEIDMUELLER CLAMP CONNECTOR

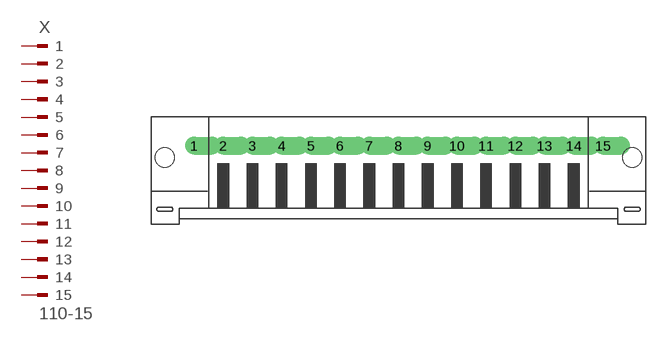
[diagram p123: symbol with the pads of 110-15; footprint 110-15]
Designator prefix X

## 110-15  [110-15]
1  1  pas
2  2  pas
3  3  pas
4  4  pas
5  5  pas
6  6  pas
7  7  pas
8  8  pas
9  9  pas
10  10  pas
11  11  pas
12  12  pas
13  13  pas
14  14  pas
15  15  pas

## Footprint 110-15 (pad centres in mm)
WEIDMUELLER CLAMP CONNECTOR
drill 1.422 offset: 1 -24.5,1.75; 2 -21,1.75; 3 -17.5,1.75; 4 -14,1.75; 5 -10.5,1.75; 6 -7,1.75; 7 -3.5,1.75; 8 0,1.75; 9 3.5,1.75; 10 7,1.75; 11 10.5,1.75; 12 14,1.75; 13 17.5,1.75; 14 21,1.75; 15 24.5,1.75
hole 2.3 at -28,0.35
hole 2.3 at 28,0.35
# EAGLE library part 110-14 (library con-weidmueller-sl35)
WEIDMUELLER CLAMP CONNECTOR

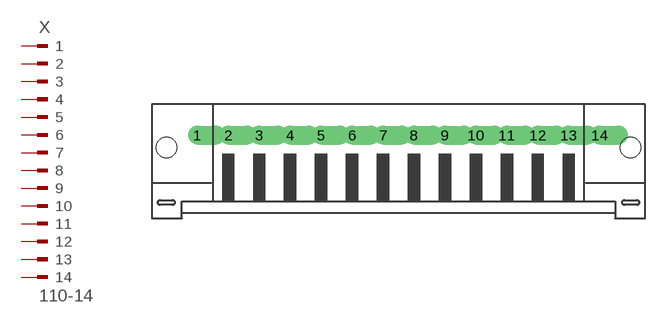
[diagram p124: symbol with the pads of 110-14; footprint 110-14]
Designator prefix X

## 110-14  [110-14]
1  1  pas
2  2  pas
3  3  pas
4  4  pas
5  5  pas
6  6  pas
7  7  pas
8  8  pas
9  9  pas
10  10  pas
11  11  pas
12  12  pas
13  13  pas
14  14  pas

## Footprint 110-14 (pad centres in mm)
WEIDMUELLER CLAMP CONNECTOR
drill 1.422 offset: 1 -22.75,1.75; 2 -19.25,1.75; 3 -15.75,1.75; 4 -12.25,1.75; 5 -8.75,1.75; 6 -5.25,1.75; 7 -1.75,1.75; 8 1.75,1.75; 9 5.25,1.75; 10 8.75,1.75; 11 12.25,1.75; 12 15.75,1.75; 13 19.25,1.75; 14 22.75,1.75
hole 2.3 at -26.25,0.35
hole 2.3 at 26.25,0.35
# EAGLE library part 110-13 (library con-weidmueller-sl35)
WEIDMUELLER CLAMP CONNECTOR

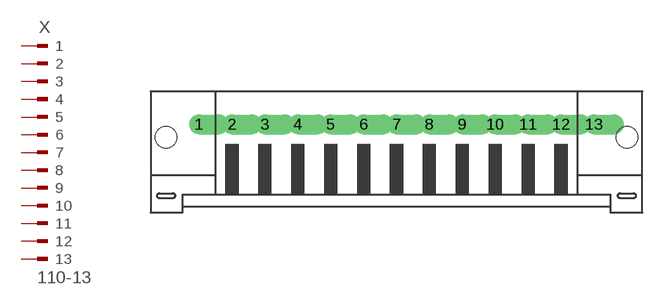
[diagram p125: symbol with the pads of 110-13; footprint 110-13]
Designator prefix X

## 110-13  [110-13]
1  1  pas
2  2  pas
3  3  pas
4  4  pas
5  5  pas
6  6  pas
7  7  pas
8  8  pas
9  9  pas
10  10  pas
11  11  pas
12  12  pas
13  13  pas

## Footprint 110-13 (pad centres in mm)
WEIDMUELLER CLAMP CONNECTOR
drill 1.422 offset: 1 -21,1.75; 2 -17.5,1.75; 3 -14,1.75; 4 -10.5,1.75; 5 -7,1.75; 6 -3.5,1.75; 7 0,1.75; 8 3.5,1.75; 9 7,1.75; 10 10.5,1.75; 11 14,1.75; 12 17.5,1.75; 13 21,1.75
hole 2.3 at -24.5,0.35
hole 2.3 at 24.5,0.35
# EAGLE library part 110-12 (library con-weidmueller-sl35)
WEIDMUELLER CLAMP CONNECTOR

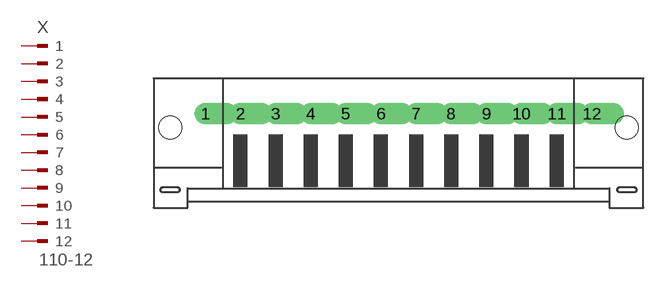
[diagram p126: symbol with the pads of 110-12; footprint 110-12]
Designator prefix X

## 110-12  [110-12]
1  1  pas
2  2  pas
3  3  pas
4  4  pas
5  5  pas
6  6  pas
7  7  pas
8  8  pas
9  9  pas
10  10  pas
11  11  pas
12  12  pas

## Footprint 110-12 (pad centres in mm)
WEIDMUELLER CLAMP CONNECTOR
drill 1.422 offset: 1 -19.25,1.75; 2 -15.75,1.75; 3 -12.25,1.75; 4 -8.75,1.75; 5 -5.25,1.75; 6 -1.75,1.75; 7 1.75,1.75; 8 5.25,1.75; 9 8.75,1.75; 10 12.25,1.75; 11 15.75,1.75; 12 19.25,1.75
hole 2.3 at -22.75,0.35
hole 2.3 at 22.75,0.35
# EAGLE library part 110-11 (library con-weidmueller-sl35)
WEIDMUELLER CLAMP CONNECTOR

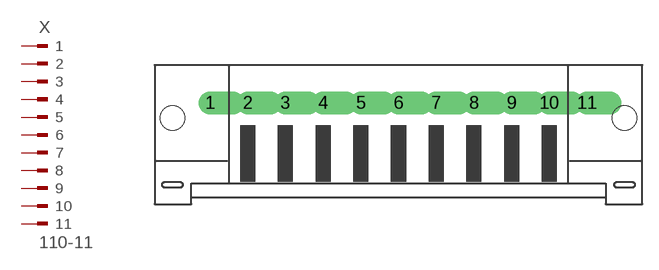
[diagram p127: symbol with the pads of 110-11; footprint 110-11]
Designator prefix X

## 110-11  [110-11]
1  1  pas
2  2  pas
3  3  pas
4  4  pas
5  5  pas
6  6  pas
7  7  pas
8  8  pas
9  9  pas
10  10  pas
11  11  pas

## Footprint 110-11 (pad centres in mm)
WEIDMUELLER CLAMP CONNECTOR
drill 1.422 offset: 1 -17.5,1.75; 2 -14,1.75; 3 -10.5,1.75; 4 -7,1.75; 5 -3.5,1.75; 6 0,1.75; 7 3.5,1.75; 8 7,1.75; 9 10.5,1.75; 10 14,1.75; 11 17.5,1.75
hole 2.3 at -21,0.35
hole 2.3 at 21,0.35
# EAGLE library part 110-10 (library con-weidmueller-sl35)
WEIDMUELLER CLAMP CONNECTOR

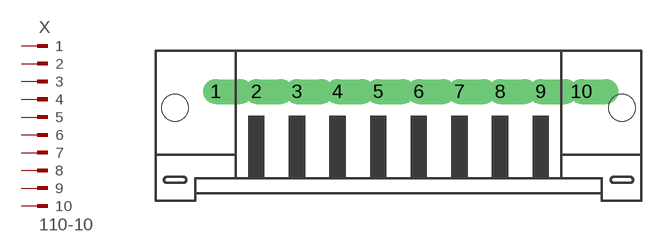
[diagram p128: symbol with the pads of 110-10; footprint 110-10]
Designator prefix X

## 110-10  [110-10]
1  1  pas
2  2  pas
3  3  pas
4  4  pas
5  5  pas
6  6  pas
7  7  pas
8  8  pas
9  9  pas
10  10  pas

## Footprint 110-10 (pad centres in mm)
WEIDMUELLER CLAMP CONNECTOR
drill 1.422 offset: 1 -15.75,1.75; 2 -12.25,1.75; 3 -8.75,1.75; 4 -5.25,1.75; 5 -1.75,1.75; 6 1.75,1.75; 7 5.25,1.75; 8 8.75,1.75; 9 12.25,1.75; 10 15.75,1.75
hole 2.3 at -19.25,0.35
hole 2.3 at 19.25,0.35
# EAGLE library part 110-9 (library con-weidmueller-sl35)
WEIDMUELLER CLAMP CONNECTOR

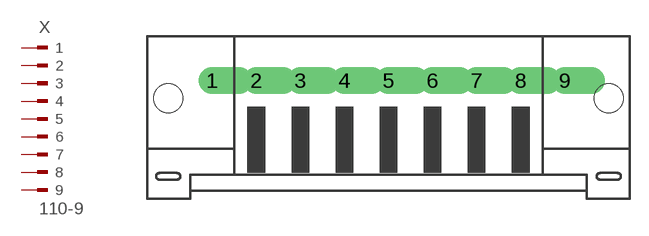
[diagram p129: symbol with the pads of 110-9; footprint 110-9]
Designator prefix X

## 110-9  [110-9]
1  1  pas
2  2  pas
3  3  pas
4  4  pas
5  5  pas
6  6  pas
7  7  pas
8  8  pas
9  9  pas

## Footprint 110-9 (pad centres in mm)
WEIDMUELLER CLAMP CONNECTOR
drill 1.422 offset: 1 -14,1.75; 2 -10.5,1.75; 3 -7,1.75; 4 -3.5,1.75; 5 0,1.75; 6 3.5,1.75; 7 7,1.75; 8 10.5,1.75; 9 14,1.75
hole 2.3 at -17.5,0.35
hole 2.3 at 17.5,0.35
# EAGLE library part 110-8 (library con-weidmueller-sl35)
WEIDMUELLER CLAMP CONNECTOR

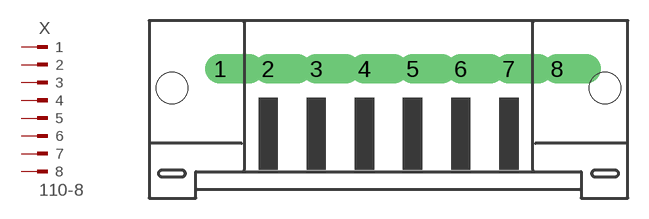
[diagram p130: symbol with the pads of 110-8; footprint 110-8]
Designator prefix X

## 110-8  [110-8]
1  1  pas
2  2  pas
3  3  pas
4  4  pas
5  5  pas
6  6  pas
7  7  pas
8  8  pas

## Footprint 110-8 (pad centres in mm)
WEIDMUELLER CLAMP CONNECTOR
drill 1.422 offset: 1 -12.25,1.75; 2 -8.75,1.75; 3 -5.25,1.75; 4 -1.75,1.75; 5 1.75,1.75; 6 5.25,1.75; 7 8.75,1.75; 8 12.25,1.75
hole 2.3 at -15.75,0.35
hole 2.3 at 15.75,0.35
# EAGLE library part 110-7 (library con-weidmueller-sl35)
WEIDMUELLER CLAMP CONNECTOR

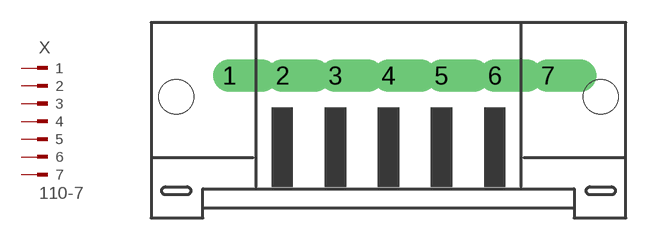
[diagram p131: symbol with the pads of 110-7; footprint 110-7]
Designator prefix X

## 110-7  [110-7]
1  1  pas
2  2  pas
3  3  pas
4  4  pas
5  5  pas
6  6  pas
7  7  pas

## Footprint 110-7 (pad centres in mm)
WEIDMUELLER CLAMP CONNECTOR
drill 1.422 offset: 1 -10.5,1.75; 2 -7,1.75; 3 -3.5,1.75; 4 0,1.75; 5 3.5,1.75; 6 7,1.75; 7 10.5,1.75
hole 2.3 at -14,0.35
hole 2.3 at 14,0.35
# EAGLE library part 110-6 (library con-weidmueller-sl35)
WEIDMUELLER CLAMP CONNECTOR

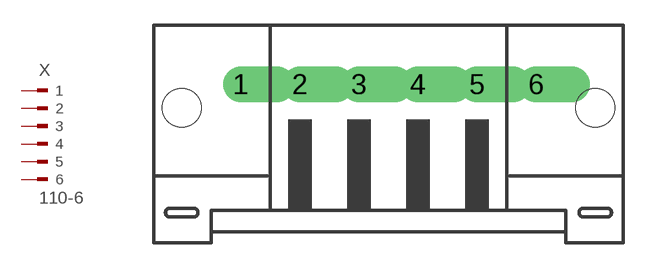
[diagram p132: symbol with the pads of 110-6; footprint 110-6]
Designator prefix X

## 110-6  [110-6]
1  1  pas
2  2  pas
3  3  pas
4  4  pas
5  5  pas
6  6  pas

## Footprint 110-6 (pad centres in mm)
WEIDMUELLER CLAMP CONNECTOR
drill 1.422 offset: 1 -8.75,1.75; 2 -5.25,1.75; 3 -1.75,1.75; 4 1.75,1.75; 5 5.25,1.75; 6 8.75,1.75
hole 2.3 at -12.25,0.35
hole 2.3 at 12.25,0.35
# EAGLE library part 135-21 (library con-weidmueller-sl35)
WEIDMUELLER CLAMP CONNECTOR

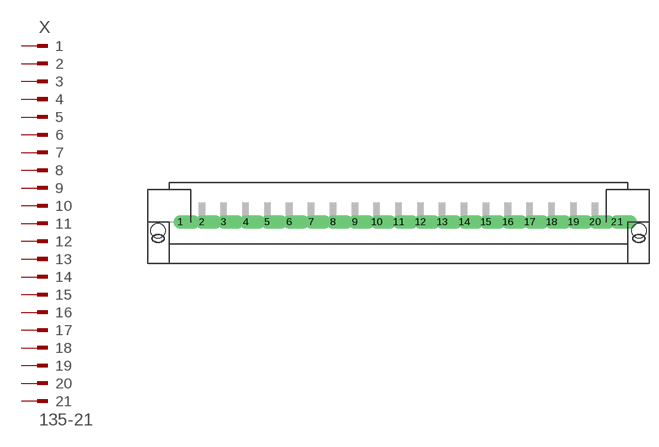
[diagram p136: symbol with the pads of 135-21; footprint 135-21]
Designator prefix X

## 135-21  [135-21]
1  1  pas
2  2  pas
3  3  pas
4  4  pas
5  5  pas
6  6  pas
7  7  pas
8  8  pas
9  9  pas
10  10  pas
11  11  pas
12  12  pas
13  13  pas
14  14  pas
15  15  pas
16  16  pas
17  17  pas
18  18  pas
19  19  pas
20  20  pas
21  21  pas

## Footprint 135-21 (pad centres in mm)
WEIDMUELLER CLAMP CONNECTOR
drill 1.422 offset: 1 -35,0; 2 -31.5,0; 3 -28,0; 4 -24.5,0; 5 -21,0; 6 -17.5,0; 7 -14,0; 8 -10.5,0; 9 -7,0; 10 -3.5,0; 11 0,0; 12 3.5,0; 13 7,0; 14 10.5,0; 15 14,0; 16 17.5,0; 17 21,0; 18 24.5,0; 19 28,0; 20 31.5,0; 21 35,0
hole 2.3 at -38.5,-1.4
hole 2.3 at 38.5,-1.4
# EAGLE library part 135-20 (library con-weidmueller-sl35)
WEIDMUELLER CLAMP CONNECTOR

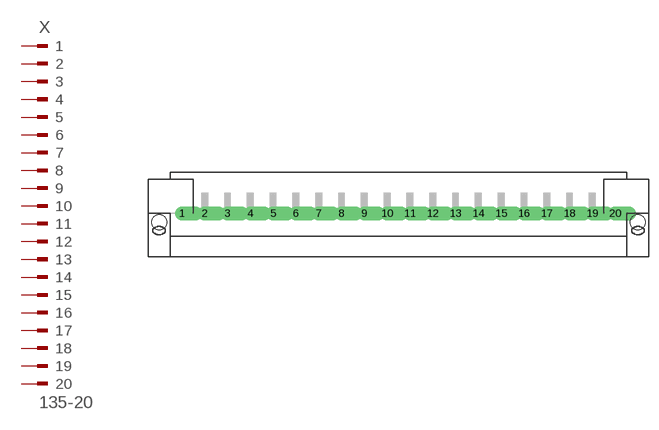
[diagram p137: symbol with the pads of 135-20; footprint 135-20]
Designator prefix X

## 135-20  [135-20]
1  1  pas
2  2  pas
3  3  pas
4  4  pas
5  5  pas
6  6  pas
7  7  pas
8  8  pas
9  9  pas
10  10  pas
11  11  pas
12  12  pas
13  13  pas
14  14  pas
15  15  pas
16  16  pas
17  17  pas
18  18  pas
19  19  pas
20  20  pas

## Footprint 135-20 (pad centres in mm)
WEIDMUELLER CLAMP CONNECTOR
drill 1.422 offset: 1 -33.25,0; 2 -29.75,0; 3 -26.25,0; 4 -22.75,0; 5 -19.25,0; 6 -15.75,0; 7 -12.25,0; 8 -8.75,0; 9 -5.25,0; 10 -1.75,0; 11 1.75,0; 12 5.25,0; 13 8.75,0; 14 12.25,0; 15 15.75,0; 16 19.25,0; 17 22.75,0; 18 26.25,0; 19 29.75,0; 20 33.25,0
hole 2.3 at -36.75,-1.4
hole 2.3 at 36.75,-1.4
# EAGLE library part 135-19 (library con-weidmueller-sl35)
WEIDMUELLER CLAMP CONNECTOR

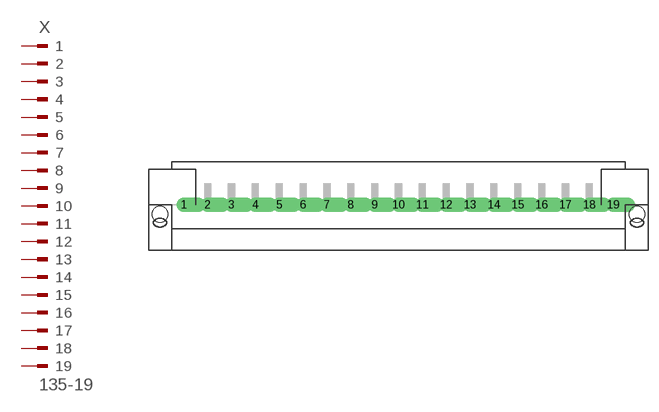
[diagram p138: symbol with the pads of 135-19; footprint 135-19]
Designator prefix X

## 135-19  [135-19]
1  1  pas
2  2  pas
3  3  pas
4  4  pas
5  5  pas
6  6  pas
7  7  pas
8  8  pas
9  9  pas
10  10  pas
11  11  pas
12  12  pas
13  13  pas
14  14  pas
15  15  pas
16  16  pas
17  17  pas
18  18  pas
19  19  pas

## Footprint 135-19 (pad centres in mm)
WEIDMUELLER CLAMP CONNECTOR
drill 1.422 offset: 1 -31.5,0; 2 -28,0; 3 -24.5,0; 4 -21,0; 5 -17.5,0; 6 -14,0; 7 -10.5,0; 8 -7,0; 9 -3.5,0; 10 0,0; 11 3.5,0; 12 7,0; 13 10.5,0; 14 14,0; 15 17.5,0; 16 21,0; 17 24.5,0; 18 28,0; 19 31.5,0
hole 2.3 at -35,-1.4
hole 2.3 at 35,-1.4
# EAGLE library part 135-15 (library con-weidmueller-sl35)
WEIDMUELLER CLAMP CONNECTOR

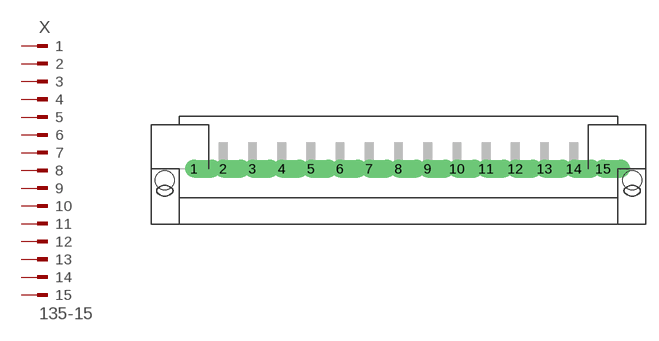
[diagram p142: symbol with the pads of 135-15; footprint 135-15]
Designator prefix X

## 135-15  [135-15]
1  1  pas
2  2  pas
3  3  pas
4  4  pas
5  5  pas
6  6  pas
7  7  pas
8  8  pas
9  9  pas
10  10  pas
11  11  pas
12  12  pas
13  13  pas
14  14  pas
15  15  pas

## Footprint 135-15 (pad centres in mm)
WEIDMUELLER CLAMP CONNECTOR
drill 1.422 offset: 1 -24.5,0; 2 -21,0; 3 -17.5,0; 4 -14,0; 5 -10.5,0; 6 -7,0; 7 -3.5,0; 8 0,0; 9 3.5,0; 10 7,0; 11 10.5,0; 12 14,0; 13 17.5,0; 14 21,0; 15 24.5,0
hole 2.3 at -28,-1.4
hole 2.3 at 28,-1.4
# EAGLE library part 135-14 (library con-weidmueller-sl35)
WEIDMUELLER CLAMP CONNECTOR

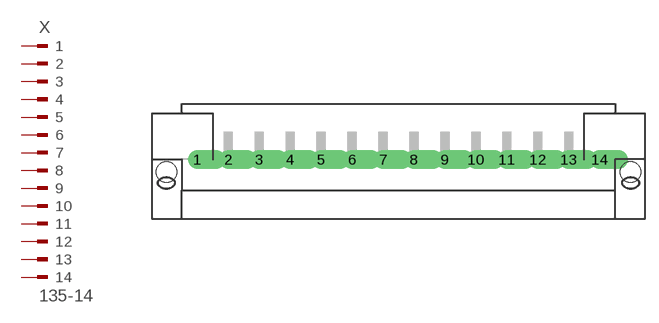
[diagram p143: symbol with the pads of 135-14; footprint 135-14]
Designator prefix X

## 135-14  [135-14]
1  1  pas
2  2  pas
3  3  pas
4  4  pas
5  5  pas
6  6  pas
7  7  pas
8  8  pas
9  9  pas
10  10  pas
11  11  pas
12  12  pas
13  13  pas
14  14  pas

## Footprint 135-14 (pad centres in mm)
WEIDMUELLER CLAMP CONNECTOR
drill 1.422 offset: 1 -22.75,0; 2 -19.25,0; 3 -15.75,0; 4 -12.25,0; 5 -8.75,0; 6 -5.25,0; 7 -1.75,0; 8 1.75,0; 9 5.25,0; 10 8.75,0; 11 12.25,0; 12 15.75,0; 13 19.25,0; 14 22.75,0
hole 2.3 at -26.25,-1.4
hole 2.3 at 26.25,-1.4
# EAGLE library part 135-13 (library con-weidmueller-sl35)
WEIDMUELLER CLAMP CONNECTOR

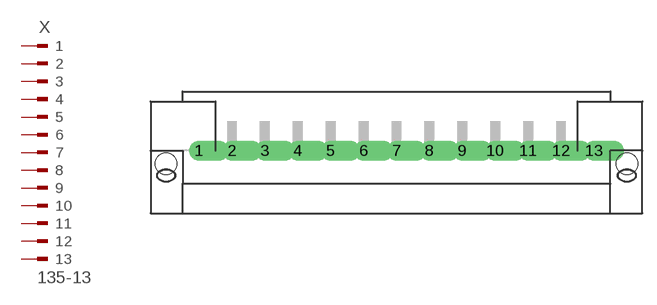
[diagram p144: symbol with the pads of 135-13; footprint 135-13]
Designator prefix X

## 135-13  [135-13]
1  1  pas
2  2  pas
3  3  pas
4  4  pas
5  5  pas
6  6  pas
7  7  pas
8  8  pas
9  9  pas
10  10  pas
11  11  pas
12  12  pas
13  13  pas

## Footprint 135-13 (pad centres in mm)
WEIDMUELLER CLAMP CONNECTOR
drill 1.422 offset: 1 -21,0; 2 -17.5,0; 3 -14,0; 4 -10.5,0; 5 -7,0; 6 -3.5,0; 7 0,0; 8 3.5,0; 9 7,0; 10 10.5,0; 11 14,0; 12 17.5,0; 13 21,0
hole 2.3 at -24.5,-1.4
hole 2.3 at 24.5,-1.4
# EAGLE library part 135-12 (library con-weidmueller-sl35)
WEIDMUELLER CLAMP CONNECTOR

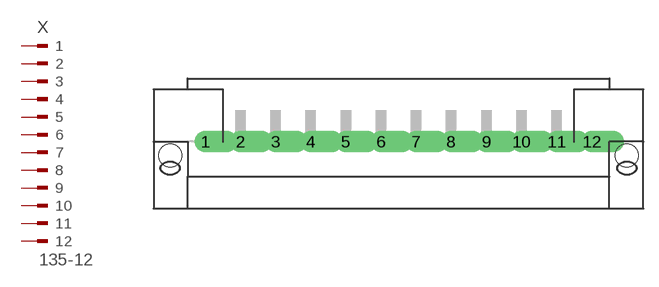
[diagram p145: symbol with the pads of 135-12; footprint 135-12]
Designator prefix X

## 135-12  [135-12]
1  1  pas
2  2  pas
3  3  pas
4  4  pas
5  5  pas
6  6  pas
7  7  pas
8  8  pas
9  9  pas
10  10  pas
11  11  pas
12  12  pas

## Footprint 135-12 (pad centres in mm)
WEIDMUELLER CLAMP CONNECTOR
drill 1.422 offset: 1 -19.25,0; 2 -15.75,0; 3 -12.25,0; 4 -8.75,0; 5 -5.25,0; 6 -1.75,0; 7 1.75,0; 8 5.25,0; 9 8.75,0; 10 12.25,0; 11 15.75,0; 12 19.25,0
hole 2.3 at -22.75,-1.4
hole 2.3 at 22.75,-1.4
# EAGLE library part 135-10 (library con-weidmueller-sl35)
WEIDMUELLER CLAMP CONNECTOR

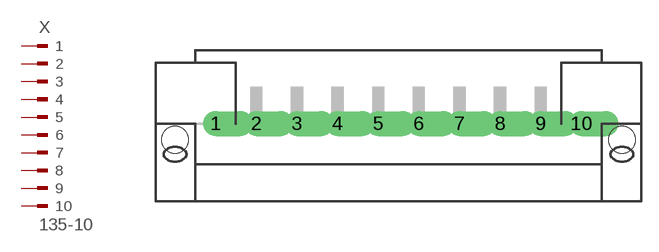
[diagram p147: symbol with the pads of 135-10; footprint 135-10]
Designator prefix X

## 135-10  [135-10]
1  1  pas
2  2  pas
3  3  pas
4  4  pas
5  5  pas
6  6  pas
7  7  pas
8  8  pas
9  9  pas
10  10  pas

## Footprint 135-10 (pad centres in mm)
WEIDMUELLER CLAMP CONNECTOR
drill 1.422 offset: 1 -15.75,0; 2 -12.25,0; 3 -8.75,0; 4 -5.25,0; 5 -1.75,0; 6 1.75,0; 7 5.25,0; 8 8.75,0; 9 12.25,0; 10 15.75,0
hole 2.3 at -19.25,-1.4
hole 2.3 at 19.25,-1.4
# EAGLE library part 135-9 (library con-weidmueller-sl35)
WEIDMUELLER CLAMP CONNECTOR

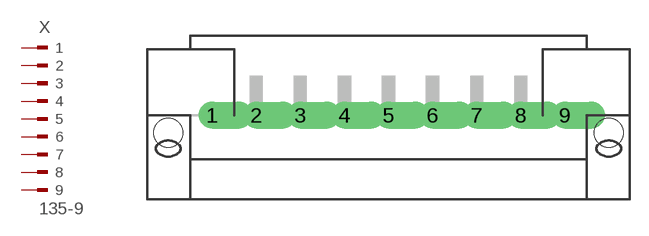
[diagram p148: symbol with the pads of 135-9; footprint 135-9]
Designator prefix X

## 135-9  [135-9]
1  1  pas
2  2  pas
3  3  pas
4  4  pas
5  5  pas
6  6  pas
7  7  pas
8  8  pas
9  9  pas

## Footprint 135-9 (pad centres in mm)
WEIDMUELLER CLAMP CONNECTOR
drill 1.422 offset: 1 -14,0; 2 -10.5,0; 3 -7,0; 4 -3.5,0; 5 0,0; 6 3.5,0; 7 7,0; 8 10.5,0; 9 14,0
hole 2.3 at -17.5,-1.4
hole 2.3 at 17.5,-1.4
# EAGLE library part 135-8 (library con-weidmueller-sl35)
WEIDMUELLER CLAMP CONNECTOR

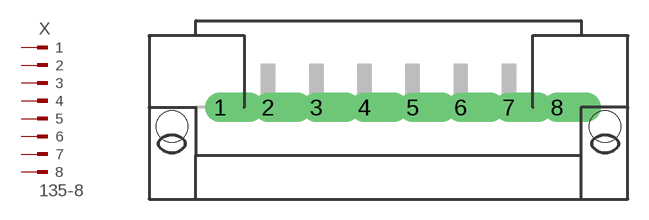
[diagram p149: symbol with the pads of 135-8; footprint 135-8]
Designator prefix X

## 135-8  [135-8]
1  1  pas
2  2  pas
3  3  pas
4  4  pas
5  5  pas
6  6  pas
7  7  pas
8  8  pas

## Footprint 135-8 (pad centres in mm)
WEIDMUELLER CLAMP CONNECTOR
drill 1.422 offset: 1 -12.25,0; 2 -8.75,0; 3 -5.25,0; 4 -1.75,0; 5 1.75,0; 6 5.25,0; 7 8.75,0; 8 12.25,0
hole 2.3 at -15.75,-1.4
hole 2.3 at 15.75,-1.4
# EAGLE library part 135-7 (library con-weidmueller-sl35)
WEIDMUELLER CLAMP CONNECTOR

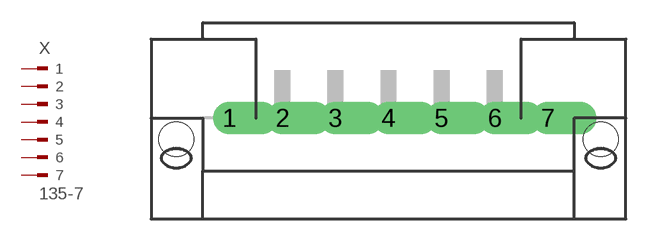
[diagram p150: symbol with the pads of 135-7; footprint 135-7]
Designator prefix X

## 135-7  [135-7]
1  1  pas
2  2  pas
3  3  pas
4  4  pas
5  5  pas
6  6  pas
7  7  pas

## Footprint 135-7 (pad centres in mm)
WEIDMUELLER CLAMP CONNECTOR
drill 1.422 offset: 1 -10.5,0; 2 -7,0; 3 -3.5,0; 4 0,0; 5 3.5,0; 6 7,0; 7 10.5,0
hole 2.3 at -14,-1.4
hole 2.3 at 14,-1.4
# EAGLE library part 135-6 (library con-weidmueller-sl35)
WEIDMUELLER CLAMP CONNECTOR

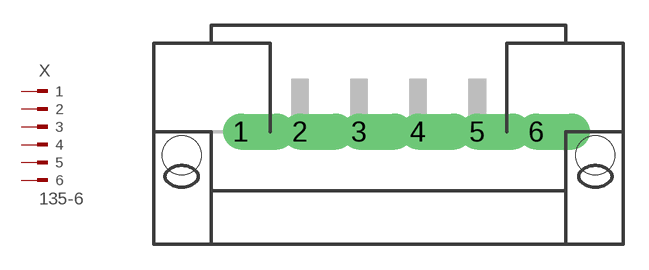
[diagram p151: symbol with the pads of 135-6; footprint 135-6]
Designator prefix X

## 135-6  [135-6]
1  1  pas
2  2  pas
3  3  pas
4  4  pas
5  5  pas
6  6  pas

## Footprint 135-6 (pad centres in mm)
WEIDMUELLER CLAMP CONNECTOR
drill 1.422 offset: 1 -8.75,0; 2 -5.25,0; 3 -1.75,0; 4 1.75,0; 5 5.25,0; 6 8.75,0
hole 2.3 at -12.25,-1.4
hole 2.3 at 12.25,-1.4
